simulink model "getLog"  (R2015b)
settings: Solver=FixedStepDiscrete  StartTime=0.0  StopTime=inf  RelTol=1e-3
StartFcn:
  | try
  |    joymex2('open',0);
  | catch
  | end
StopFcn:
  | clear joymex2

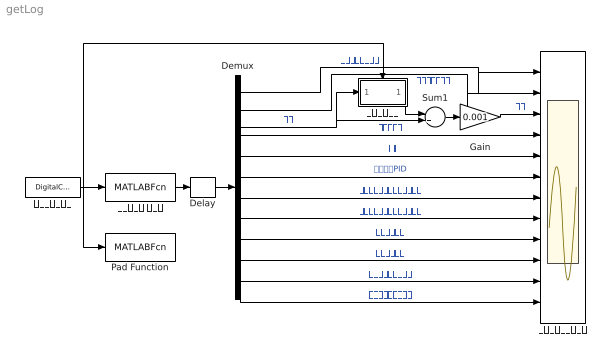
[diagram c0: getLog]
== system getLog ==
  Delay : Delay  DelayLength=1
  Demux : Demux  Outputs=12
  Gain : Gain  Gain=0.001
  Pad Function : MATLABFcn  MATLABFcn=getPadInput  OutputDimensions=0
  Sum1 : Sum  Inputs=-+|
  ロボット側 データ : MATLABFcn  MATLABFcn=getOutputPortData  OutputDimensions=12
  ロボット出力データ : Scope  NumInputPorts=12
  動作用クロック : DigitalClock  SampleTime=0.5
  右折トリガー : Subsystem  TreatAsAtomicUnit=on
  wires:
  Demux/1 -> ロボット出力データ/1  "直進加速度指示値"
  Demux/2 -> ロボット出力データ/2  "旋回速度指示値"
  ロボット側 データ/1 -> Delay/1
  Sum1/1 -> Gain/1
  右折トリガー/1(Out1) -> Sum1/1
  Gain/1 -> ロボット出力データ/3  "時間"
  Demux/7 -> ロボット出力データ/7  "姿勢制御前右車輪角度指示値"
  Demux/6 -> ロボット出力データ/6  "ジャイロPID"
  Demux/5 -> ロボット出力データ/5  "車体角度"
  Demux/4 -> ロボット出力データ/4  "車体角速度"
  Demux/3 -> Sum1/2, 右折トリガー/1(In1)  "時間"
  Demux/8 -> ロボット出力データ/8  "姿勢制御前左車輪角度指示値"
  Demux/9 -> ロボット出力データ/9  "右車輪回転角"
  Demux/10 -> ロボット出力データ/10  "左車輪回転角"
  Demux/11 -> ロボット出力データ/11  "右コントローラ出力"
  Demux/12 -> ロボット出力データ/12  "左コントローラ出力"
  動作用クロック/1 -> 右折トリガー/Trigger, Pad Function/1, ロボット側 データ/1
  Delay/1 -> Demux/1

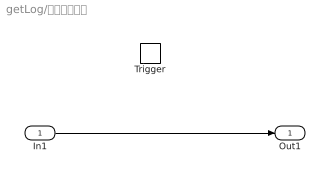
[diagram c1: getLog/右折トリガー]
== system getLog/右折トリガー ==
  In1 : Inport
  Trigger : TriggerPort
  Out1 : Outport
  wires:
  In1/1 -> Out1/1
